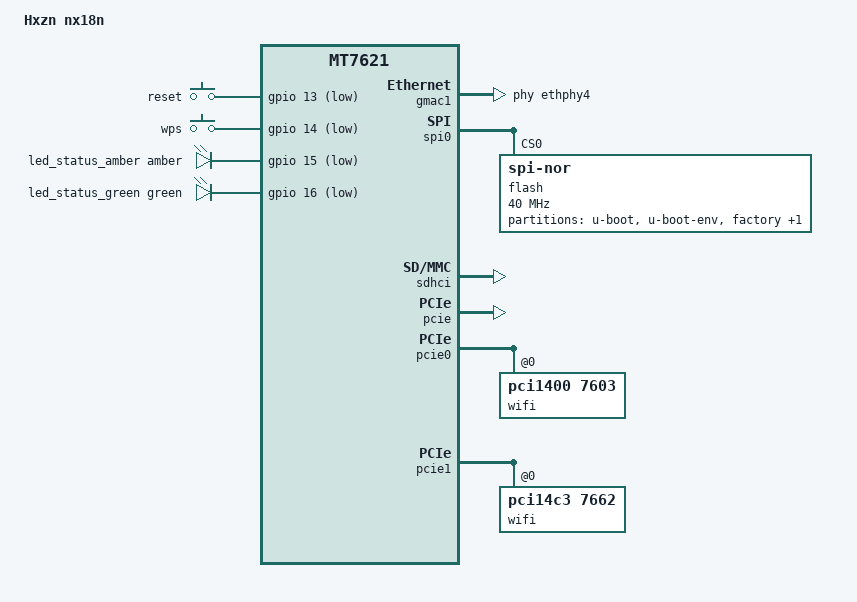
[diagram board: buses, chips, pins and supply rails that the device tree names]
// SPDX-License-Identifier: GPL-2.0-or-later OR MIT

#include "mt7621.dtsi"

#include <dt-bindings/gpio/gpio.h>
#include <dt-bindings/input/input.h>

/ {
	compatible = "hxzn,nx18n", "mediatek,mt7621-soc";
	model = "Hxzn nx18n";

	aliases {
		led-boot = &led_sys;
		led-failsafe = &led_sys;
		led-running = &led_sys;
		led-upgrade = &led_sys;
	};

	chosen {
		bootargs = "console=ttyS0,115200";
	};

	keys {
		compatible = "gpio-keys";

		reset {
			label = "reset";
			gpios = <&gpio 13 GPIO_ACTIVE_LOW>;
			linux,code = <KEY_RESTART>;
		};

		wps {
			label = "wps";
			gpios = <&gpio 14 GPIO_ACTIVE_LOW>;
			linux,code = <KEY_WPS_BUTTON>;
		};
	};

	leds {
		compatible = "gpio-leds";

		led_status_amber: led-0 {
			color = <LED_COLOR_ID_AMBER>;
			function = LED_FUNCTION_STATUS;
			gpios = <&gpio 15 GPIO_ACTIVE_LOW>;
		};

		led_status_green: led-1 {
			color = <LED_COLOR_ID_GREEN>;
			function = LED_FUNCTION_STATUS;
			gpios = <&gpio 16 GPIO_ACTIVE_LOW>;
		};
	};
};

&gmac1 {
	status = "okay";
	label = "wan";
	phy-handle = <&ethphy4>;
};

&spi0 {
	status = "okay";

	flash@0 {
		compatible = "jedec,spi-nor";
		reg = <0>;
		spi-max-frequency = <40000000>;
		broken-flash-reset;

		partitions {
			compatible = "fixed-partitions";
			#address-cells = <1>;
			#size-cells = <1>;

			partition@0 {
				label = "u-boot";
				reg = <0x0 0x30000>;
				read-only;
			};

			partition@30000 {
				label = "u-boot-env";
				reg = <0x30000 0x10000>;
				read-only;
			};

			factory: partition@40000 {
				label = "factory";
				reg = <0x40000 0x10000>;
				read-only;
			};

			partition@50000 {
				compatible = "denx,uimage";
				label = "firmware";
				reg = <0x50000 0x1fb0000>;
			};
		};
	};
};

&sdhci {
	status = "okay";
};

&pcie {
	status = "okay";
};

&pcie0 {
	wifi@0,0 {
		compatible = "pci1400,7603";
		reg = <0x0000 0 0 0 0>;
		mediatek,mtd-eeprom = <&factory 0x0000>;
	};
};

&pcie1 {
	wifi@0,0 {
		compatible = "pci14c3,7662";
		reg = <0x0000 0 0 0 0>;
		mediatek,mtd-eeprom = <&factory 0x8000>;
		ieee80211-freq-limit = <5000000 6000000>;
	};
};

&gmac0 {
	mtd-mac-address = <&factory 0xe000>;
};

&switch0 {
	ports {
		port@1 {
			status = "okay";
			label = "lan1";
		};

		port@2 {
			status = "okay";
			label = "lan2";
		};

		port@3 {
			status = "okay";
			label = "lan3";
		};

&state_default {
	gpio {
		groups = "wdt", "rgmii2";
		function = "gpio";
	};
};
